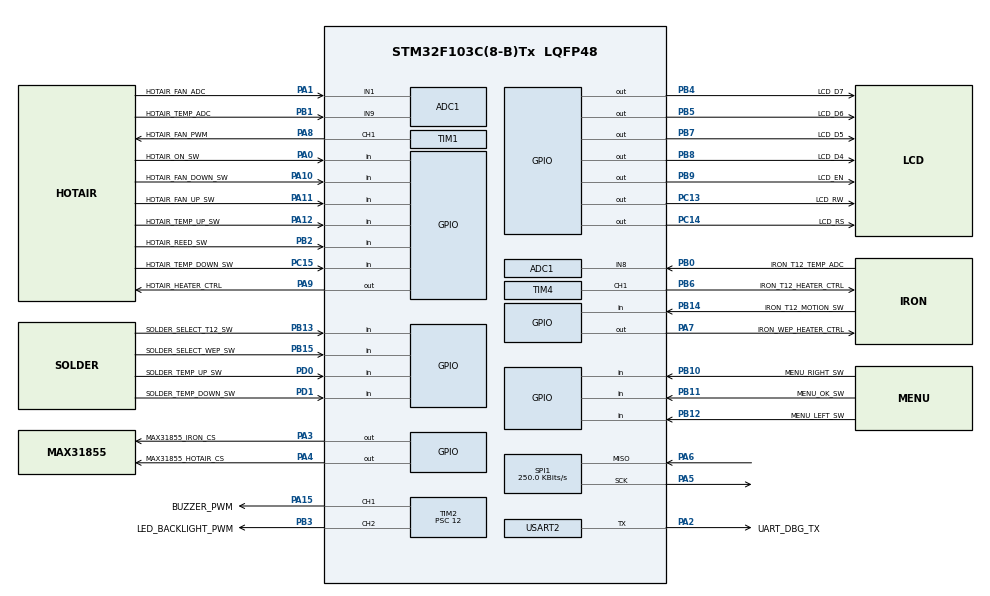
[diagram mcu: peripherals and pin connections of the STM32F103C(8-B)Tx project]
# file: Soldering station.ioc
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ADC1.Channel-0\#ChannelRegularConversion=ADC_CHANNEL_1
ADC1.ContinuousConvMode=DISABLE
ADC1.EnableRegularConversion=ENABLE
ADC1.NbrOfConversionFlag=1
ADC1.Rank-0\#ChannelRegularConversion=1
ADC1.SamplingTime-0\#ChannelRegularConversion=ADC_SAMPLETIME_1CYCLE_5
ADC1.master=1
FREERTOS.Tasks01=defaultTask,24,128,StartDefaultTask,Default,NULL,Dynamic,NULL,NULL
FREERTOS.configUSE_NEWLIB_REENTRANT=1
Mcu.Family=STM32F1
Mcu.Name=STM32F103C(8-B)Tx
Mcu.Package=LQFP48
NVIC.PriorityGroup=NVIC_PRIORITYGROUP_4
PA0-WKUP.GPIO_Label=HOTAIR_ON_SW
PA0-WKUP.GPIO_PuPd=GPIO_NOPULL
PA0-WKUP.Signal=GPIO_Input
PA1.GPIO_Label=HOTAIR_FAN_ADC
PA1.Signal=ADCx_IN1
PA10.GPIO_Label=HOTAIR_FAN_DOWN_SW
PA10.Signal=GPIO_Input
PA11.GPIO_Label=HOTAIR_FAN_UP_SW
PA11.Signal=GPIO_Input
PA12.GPIO_Label=HOTAIR_TEMP_UP_SW
PA12.Signal=GPIO_Input
PA13.GPIO_Label=SWDIO
PA13.Mode=Serial_Wire
PA13.Signal=SYS_JTMS-SWDIO
PA14.GPIO_Label=SWCLK
PA14.Mode=Serial_Wire
PA14.Signal=SYS_JTCK-SWCLK
PA15.GPIO_Label=BUZZER_PWM
PA15.Signal=S_TIM2_CH1_ETR
PA2.GPIO_Label=UART_DBG_TX
PA2.GPIO_Speed=GPIO_SPEED_FREQ_LOW
PA2.Mode=Half_duplex(single_wire_mode)
PA2.Signal=USART2_TX
PA3.GPIO_Label=MAX31855_IRON_CS
PA3.Signal=GPIO_Output
PA4.GPIO_Label=MAX31855_HOTAIR_CS
PA4.Signal=GPIO_Output
PA5.Mode=RX_Only_Simplex_Unidirect_Master
PA5.Signal=SPI1_SCK
PA6.GPIO_PuPd=GPIO_PULLDOWN
PA6.Mode=RX_Only_Simplex_Unidirect_Master
PA6.Signal=SPI1_MISO
PA7.GPIO_Label=IRON_WEP_HEATER_CTRL
PA7.GPIO_Speed=GPIO_SPEED_FREQ_HIGH
PA7.PinState=GPIO_PIN_RESET
PA7.Signal=GPIO_Output
PA8.GPIO_Label=HOTAIR_FAN_PWM
PA8.Signal=S_TIM1_CH1
PA9.GPIO_Label=HOTAIR_HEATER_CTRL
PA9.Signal=GPIO_Output
PB0.GPIO_Label=IRON_T12_TEMP_ADC
PB0.Signal=ADCx_IN8
PB1.GPIO_Label=HOTAIR_TEMP_ADC
PB1.Signal=ADCx_IN9
PB10.GPIO_Label=MENU_RIGHT_SW
PB10.Signal=GPIO_Input
PB11.GPIO_Label=MENU_OK_SW
PB11.Signal=GPIO_Input
PB12.GPIO_Label=MENU_LEFT_SW
PB12.Signal=GPIO_Input
PB13.GPIO_Label=SOLDER_SELECT_T12_SW
PB13.Signal=GPIO_Input
PB14.GPIO_Label=IRON_T12_MOTION_SW
PB14.Signal=GPIO_Input
PB15.GPIO_Label=SOLDER_SELECT_WEP_SW
PB15.Signal=GPIO_Input
PB2.GPIO_Label=HOTAIR_REED_SW
PB2.Signal=GPIO_Input
PB3.GPIO_Label=LED_BACKLIGHT_PWM
PB3.Signal=S_TIM2_CH2
PB4.GPIO_Label=LCD_D7
PB4.Signal=GPIO_Output
PB5.GPIO_Label=LCD_D6
PB5.Signal=GPIO_Output
PB6.GPIO_Label=IRON_T12_HEATER_CTRL
PB6.Signal=S_TIM4_CH1
PB7.GPIO_Label=LCD_D5
PB7.Signal=GPIO_Output
PB8.GPIO_Label=LCD_D4
PB8.Signal=GPIO_Output
PB9.GPIO_Label=LCD_EN
PB9.Signal=GPIO_Output
PC13-TAMPER-RTC.GPIO_Label=LCD_RW
PC13-TAMPER-RTC.Signal=GPIO_Output
PC14-OSC32_IN.GPIO_Label=LCD_RS
PC14-OSC32_IN.Signal=GPIO_Output
PC15-OSC32_OUT.GPIO_Label=HOTAIR_TEMP_DOWN_SW
PC15-OSC32_OUT.Signal=GPIO_Input
PD0-OSC_IN.GPIO_Label=SOLDER_TEMP_UP_SW
PD0-OSC_IN.Signal=GPIO_Input
PD1-OSC_OUT.GPIO_Label=SOLDER_TEMP_DOWN_SW
PD1-OSC_OUT.Signal=GPIO_Input
ProjectManager.HeapSize=0x200
ProjectManager.StackSize=0x400
ProjectManager.TargetToolchain=STM32CubeIDE
RCC.ADCPresc=RCC_ADCPCLK2_DIV4
RCC.AHBFreq_Value=32000000
RCC.APB1CLKDivider=RCC_HCLK_DIV2
RCC.APB1Freq_Value=16000000
RCC.APB1TimFreq_Value=32000000
RCC.APB2Freq_Value=32000000
RCC.APB2TimFreq_Value=32000000
RCC.HCLKFreq_Value=32000000
RCC.PLLMUL=RCC_PLL_MUL8
RCC.SYSCLKFreq_VALUE=32000000
RCC.SYSCLKSource=RCC_SYSCLKSOURCE_PLLCLK
RCC.USBFreq_Value=32000000
SH.ADCx_IN1.0=ADC1_IN1,IN1
SH.ADCx_IN8.0=ADC1_IN8,IN8
SH.ADCx_IN9.0=ADC1_IN9,IN9
SH.S_TIM1_CH1.0=TIM1_CH1,PWM Generation1 CH1
SH.S_TIM2_CH1_ETR.0=TIM2_CH1,PWM Generation1 CH1
SH.S_TIM2_CH2.0=TIM2_CH2,PWM Generation2 CH2
SH.S_TIM4_CH1.0=TIM4_CH1,PWM Generation1 CH1
SPI1.BaudRatePrescaler=SPI_BAUDRATEPRESCALER_128
SPI1.CalculateBaudRate=250.0 KBits/s
SPI1.Direction=SPI_DIRECTION_2LINES_RXONLY
SPI1.Mode=SPI_MODE_MASTER
SPI1.VirtualType=VM_MASTER
TIM1.Channel-PWM\ Generation1\ CH1=TIM_CHANNEL_1
TIM1.Period=500
TIM1.Prescaler=20
TIM1.Pulse-PWM\ Generation1\ CH1=250
TIM2.Channel-PWM\ Generation1\ CH1=TIM_CHANNEL_1
TIM2.Channel-PWM\ Generation2\ CH2=TIM_CHANNEL_2
TIM2.Period=1000
TIM2.Prescaler=12
TIM2.Pulse-PWM\ Generation1\ CH1=500
TIM2.Pulse-PWM\ Generation2\ CH2=500
TIM3.Period=65535
TIM3.Prescaler=16
TIM4.Channel-PWM\ Generation1\ CH1=TIM_CHANNEL_1
TIM4.Period=200
TIM4.Prescaler=8
TIM4.Pulse-PWM\ Generation1\ CH1=100
USART2.BaudRate=9600
USART2.Mode=MODE_TX
USART2.VirtualMode=VM_ASYNC
VP_ADC1_Vref_Input.Mode=IN-Vrefint
VP_FREERTOS_VS_CMSIS_V2.Mode=CMSIS_V2
VP_TIM1_VS_ClockSourceINT.Mode=Internal
VP_TIM2_VS_ClockSourceINT.Mode=Internal
VP_TIM3_VS_ClockSourceINT.Mode=Internal
VP_TIM4_VS_ClockSourceINT.Mode=Internal
board=custom

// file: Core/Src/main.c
/* USER CODE BEGIN Header */
/**
  ******************************************************************************
  * @file           : main.c
  * @brief          : Main program body
  ******************************************************************************
  * @attention
  *
  * Copyright (c) 2022 STMicroelectronics.
  * All rights reserved.
  *
  * This software is licensed under terms that can be found in the LICENSE file
  * in the root directory of this software component.
  * If no LICENSE file comes with this software, it is provided AS-IS.
  *
  ******************************************************************************
  */
/* USER CODE END Header */
#include "main.h"
#include "cmsis_os.h"
#include "adc.h"
#include "spi.h"
#include "tim.h"
#include "usart.h"
#include "gpio.h"

/* USER CODE BEGIN Includes */
#include <stdio.h>
#include <string.h>
#include "retarget.h"
#include "LCD16x2/LCD.h"
#include "MAX31855/MAX31855.h"
#include "utils.h"
#include "test_wep.h"
#include "adc_functions.h"
#include "test_t12.h"
#include "test_buttons.h"

#include "Buttons/buttons.h"

/* USER CODE END Includes */

void SystemClock_Config(void);
void MX_FREERTOS_Init(void);

/* USER CODE BEGIN 0 */
void button_short_pressed_test()
{
	static int i = 0;
	LCD_Clear();
	char buf[12];
	snprintf(buf, 12, "BUTTON S:%d", i);
	LCD_Puts(0,0, buf);
	i++;
}

void button_long_pressed_test()
{
	static int i = 0;
	LCD_Clear();
	char buf[12];
	snprintf(buf, 12, "BUTTON L:%d", i);
	LCD_Puts(0,1, buf);
	i++;
}
/* USER CODE END 0 */

int main(void)
{

  /* MCU Configuration--------------------------------------------------------*/

  /* Reset of all peripherals, Initializes the Flash interface and the Systick. */
  HAL_Init();

  /* Configure the system clock */
  SystemClock_Config();

  /* Initialize all configured peripherals */
  MX_GPIO_Init();
  MX_ADC1_Init();
  MX_SPI1_Init();
  MX_TIM1_Init();
  MX_TIM2_Init();
  MX_TIM3_Init();
  MX_TIM4_Init();
  MX_USART2_UART_Init();
  /* USER CODE BEGIN 2 */
  Start_generic_timer();

  //Init printf retarget
  RetargetInit(&huart2);

  //Init LCD display
  LCD_Init();
  LCD_DisplayOn();
  LCD_Clear();

  Init_ADC();

  printf("Hello! \r\n");

  // Test buttons
  button_pressed_short_cb(BUTTON_HOTAIR_FAN_UP, button_short_pressed_test);
  button_pressed_long_cb(BUTTON_HOTAIR_FAN_DOWN, button_long_pressed_test);

  /* USER CODE END 2 */

  /* Init scheduler */
  osKernelInitialize();  /* Call init function for freertos objects (in freertos.c) */
  MX_FREERTOS_Init();

  /* Start scheduler */
  osKernelStart();

  /* We should never get here as control is now taken by the scheduler */
  /* Infinite loop */
  while(1)
  {

    /* USER CODE BEGIN 3 */

	 Test_WEP();
	 Test_T12();
	 Test_HOTAIR();
	 Test_Buttons();

  }
  /* USER CODE END 3 */
}

void SystemClock_Config(void)
{
  RCC_OscInitTypeDef RCC_OscInitStruct = {0};
  RCC_ClkInitTypeDef RCC_ClkInitStruct = {0};
  RCC_PeriphCLKInitTypeDef PeriphClkInit = {0};

  /** Initializes the RCC Oscillators according to the specified parameters
  * in the RCC_OscInitTypeDef structure.
  */
  RCC_OscInitStruct.OscillatorType = RCC_OSCILLATORTYPE_HSI;
  RCC_OscInitStruct.HSIState = RCC_HSI_ON;
  RCC_OscInitStruct.HSICalibrationValue = RCC_HSICALIBRATION_DEFAULT;
  RCC_OscInitStruct.PLL.PLLState = RCC_PLL_ON;
  RCC_OscInitStruct.PLL.PLLSource = RCC_PLLSOURCE_HSI_DIV2;
  RCC_OscInitStruct.PLL.PLLMUL = RCC_PLL_MUL8;
  if (HAL_RCC_OscConfig(&RCC_OscInitStruct) != HAL_OK)
  {
    Error_Handler();
  }

  /** Initializes the CPU, AHB and APB buses clocks
  */
  RCC_ClkInitStruct.ClockType = RCC_CLOCKTYPE_HCLK|RCC_CLOCKTYPE_SYSCLK
                              |RCC_CLOCKTYPE_PCLK1|RCC_CLOCKTYPE_PCLK2;
  RCC_ClkInitStruct.SYSCLKSource = RCC_SYSCLKSOURCE_PLLCLK;
  RCC_ClkInitStruct.AHBCLKDivider = RCC_SYSCLK_DIV1;
  RCC_ClkInitStruct.APB1CLKDivider = RCC_HCLK_DIV1;
  RCC_ClkInitStruct.APB2CLKDivider = RCC_HCLK_DIV1;

  if (HAL_RCC_ClockConfig(&RCC_ClkInitStruct, FLASH_LATENCY_1) != HAL_OK)
  {
    Error_Handler();
  }
  PeriphClkInit.PeriphClockSelection = RCC_PERIPHCLK_ADC;
  PeriphClkInit.AdcClockSelection = RCC_ADCPCLK2_DIV4;
  if (HAL_RCCEx_PeriphCLKConfig(&PeriphClkInit) != HAL_OK)
  {
    Error_Handler();
  }
}

void Error_Handler(void)
{
  __disable_irq();
  while (1)
  {
  }
}

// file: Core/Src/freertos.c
/* USER CODE BEGIN Header */
/**
  ******************************************************************************
  * File Name          : freertos.c
  * Description        : Code for freertos applications
  ******************************************************************************
  * @attention
  *
  * Copyright (c) 2022 STMicroelectronics.
  * All rights reserved.
  *
  * This software is licensed under terms that can be found in the LICENSE file
  * in the root directory of this software component.
  * If no LICENSE file comes with this software, it is provided AS-IS.
  *
  ******************************************************************************
  */
/* USER CODE END Header */

#include "FreeRTOS.h"
#include "task.h"
#include "main.h"
#include "cmsis_os.h"

/* Definitions for defaultTask */
osThreadId_t defaultTaskHandle;
const osThreadAttr_t defaultTask_attributes = {
  .name = "defaultTask",
  .stack_size = 128 * 4,
  .priority = (osPriority_t) osPriorityNormal,
};

void StartDefaultTask(void *argument);

void MX_FREERTOS_Init(void); /* (MISRA C 2004 rule 8.1) */

void MX_FREERTOS_Init(void) {

  /* Create the thread(s) */
  /* creation of defaultTask */
  defaultTaskHandle = osThreadNew(StartDefaultTask, NULL, &defaultTask_attributes);

  /* USER CODE BEGIN RTOS_THREADS */
  /* add threads, ... */
  //buttonsTaskHandle = osThreadNew(buttons_task, NULL, &buttonsTask_attributes);
  /* USER CODE END RTOS_THREADS */

}

void StartDefaultTask(void *argument)
{
  for(;;)
  {
    osDelay(1);
  }
}
